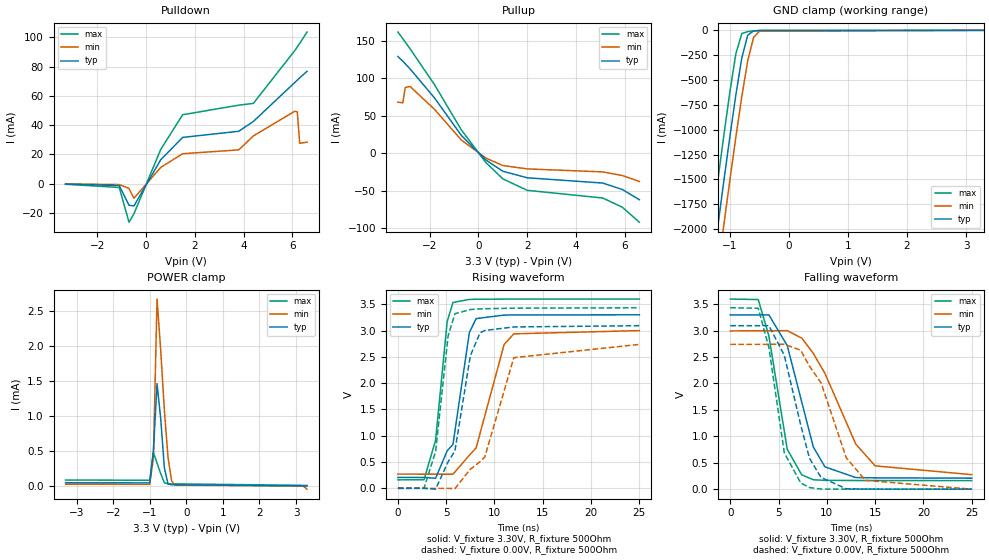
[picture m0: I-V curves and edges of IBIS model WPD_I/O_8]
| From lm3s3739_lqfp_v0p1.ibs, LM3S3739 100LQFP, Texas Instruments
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[Model]   WPD_I/O_8
Model_type   I/O
Vinl = 1.26
Vinh = 2.04
Vmeas = 1.65
| variable   typ   min   max
C_comp   9.739pF   9.739pF   9.803pF
[Model Spec]
Vinh+   1.91   1.78   2.04
Vinh-   1.90   1.76   2.03
Vinl+   1.40   1.27   1.54
Vinl-   1.39   1.26   1.53
| variable   typ   min   max
[Temperature Range]  25   85   -40
[Voltage Range]   3.3V   3.0V   3.6V
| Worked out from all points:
|   slope of the pulldown table from 0 to 0.495 V, typ, clamps not added: 35.8 ohm
|   slope of the pullup table from 0 to 0.495 V, typ, clamps not added: 35.8 ohm
|   GND clamp passes 1 mA (typ) near -0.48 V on its own axis
|   POWER clamp passes 1 mA (typ) near -0.71 V on its own axis
|   falling waveform, V_fixture 3.30V, R_fixture 500Ohm: 20-80 % time 2.57ns typ, 3.82ns min, 1.8ns max; typ from 3.3 V to 0.208 V
|   rising waveform, V_fixture 3.30V, R_fixture 500Ohm: 20-80 % time 1.54ns typ, 2.24ns min, 1.14ns max; typ from 0.208 V to 3.3 V
|   falling waveform, V_fixture 0.00V, R_fixture 500Ohm: 20-80 % time 2.29ns typ, 3.1ns min, 1.68ns max; typ from 3.09 V to 0 V
|   rising waveform, V_fixture 0.00V, R_fixture 500Ohm: 20-80 % time 1.64ns typ, 2.39ns min, 1.21ns max; typ from 0 V to 3.09 V
[Pulldown]
|  Voltage   I(typ)   I(min)   I(max)
-3.3V     -256.5uA   -145.6uA   -364.4uA
-1.1V     -1.273mA   -587.4uA   -2.566mA
-700mV    -14.71mA   -3.214mA   -26.32mA
-500mV    -15.25mA   -9.999mA   -20.65mA
600mV     16.35mA    11.13mA    23.4mA
1.5V      31.67mA    20.51mA    47.18mA
3.8V      35.87mA    23.14mA    53.71mA
4.4V      42.58mA    32.68mA    54.95mA
6.1V      69.24mA    49.59mA    91.09mA
6.2V      70.82mA    49.16mA    93.48mA
6.3V      72.4mA     27.65mA    95.95mA
6.6V      76.88mA    28.4mA     103.7mA
[Pullup]
|  Voltage   I(typ)   I(min)   I(max)
-3.3V     129.3mA    68.2mA     161.9mA
-3.1V     122.9mA    67.4mA     153.1mA
-3V       119.6mA    87.82mA    148.6mA
-2.8V     112.6mA    89.2mA     139.5mA
-1.8V     73.96mA    58.72mA    91.63mA
-700mV    23.81mA    17.72mA    31.26mA
300mV     -8.861mA   -6.312mA   -12.18mA
1V        -24.01mA   -16.38mA   -34.13mA
2V        -32.74mA   -20.87mA   -49.48mA
5.1V      -39.81mA   -24.88mA   -59.77mA
5.9V      -48.4mA    -29.75mA   -72.06mA
6.6V      -62.06mA   -37.61mA   -92.08mA
[GND Clamp]
|  Voltage   I(typ)   I(min)   I(max)
-3.3V     -11.73A    -12.14A    -11.32A
-1.4V     -2.85A     -3.29A     -2.391A
-1.3V     -2.393A    -2.835A    -1.933A
-1.2V     -1.942A    -2.383A    -1.481A
-1.1V     -1.496A    -1.937A    -1.038A
-1V       -1.061A    -1.498A    -612.1mA
-900mV    -646.5mA   -1.071A    -233.9mA
-800mV    -278.2mA   -665.9mA   -32.18mA
-700mV    -49.13mA   -307.7mA   -12.5mA
-600mV    -5.766mA   -70.86mA   -6.513mA
-500mV    -1.212mA   -8.171mA   -2.264mA
3.3V      16.11uA    11.95uA    29.77uA
[POWER Clamp]
|  Voltage   I(typ)   I(min)   I(max)
-3.3V     45.95uA    24.7uA     84.99uA
-1V       43.79uA    23.54uA    81.02uA
-900mV    497uA      400.5uA    481.3uA
-800mV    1.464mA    2.675mA    328uA
-700mV    965.7uA    1.944mA    175.8uA
-600mV    259.3uA    1.087mA    45.21uA
-500mV    29.01uA    407.8uA    31.06uA
-400mV    16.44uA    70.61uA    29.85uA
-300mV    16.12uA    11.95uA    29.79uA
3.1V      2.407uA    -925.9nA   9.193uA
3.2V      1.227uA    -4.064uA   7.471uA
3.3V      -117.9pA   -46.06uA   5.69uA
[Ramp]
| variable   typ   min   max
dV/dt_f   1.85/2.57n   1.63/3.82n   2.06/1.80n
dV/dt_r   1.86/1.64n   1.63/2.39n   2.06/1.21n
R_load = 500Ohm
[Falling Waveform]
V_fixture = 3.30V
V_fixture_min = 3.00V
V_fixture_max = 3.60V
R_fixture = 500Ohm
|   Time   V(typ)   V(min)   V(max)
0s        3.298V     2.994V     3.597V
2.9ns     3.298V     2.998V     3.588V
4ns       3.298V     2.998V     2.898V
5.9ns     2.717V     2.999V     754.8mV
7.4ns     1.65V      2.859V     271.3mV
8.6ns     799.3mV    2.568V     178.4mV
9.8ns     422.5mV    2.192V     166.9mV
13ns      219mV      852mV      163.9mV
15ns      214mV      441.3mV    163.3mV
25ns      208.2mV    274.5mV    162.3mV
[Rising Waveform]
V_fixture = 3.30V
V_fixture_min = 3.00V
V_fixture_max = 3.60V
R_fixture = 500Ohm
|   Time   V(typ)   V(min)   V(max)
0s        207.6mV    271.4mV    162.2mV
2.7ns     207.4mV    270.4mV    165.3mV
3.9ns     191.8mV    270.1mV    914mV
5.1ns     714.8mV    269.9mV    3.171V
5.7ns     836.9mV    269.3mV    3.533V
7.4ns     2.965V     630.1mV    3.591V
8.1ns     3.227V     771.5mV    3.594V
11ns      3.294V     2.736V     3.597V
12ns      3.296V     2.937V     3.597V
25ns      3.299V     2.999V     3.598V
[Falling Waveform]
V_fixture = 0.00V
V_fixture_min = 0.00V
V_fixture_max = 0.00V
R_fixture = 500Ohm
|   Time   V(typ)   V(min)   V(max)
0s        3.093V     2.739V     3.433V
2.9ns     3.093V     2.74V      3.423V
4ns       3.094V     2.741V     2.68V
5.6ns     2.532V     2.741V     685.6mV
7.3ns     1.21V      2.629V     116.7mV
8.2ns     586.3mV    2.327V     30.35mV
9.4ns     222.8mV    2.013V     1.741mV
12ns      7.855mV    597.6mV    107.7uV
14ns      1.389mV    166.7mV    70.3uV
25ns      37.48uV    42.83uV    16.46uV
[Rising Waveform]
V_fixture = 0.00V
V_fixture_min = 0.00V
V_fixture_max = 0.00V
R_fixture = 500Ohm
|   Time   V(typ)   V(min)   V(max)
0s        364.4uV    12.24mV    108.2uV
2.7ns     122.3uV    1.727mV    4.268mV
3.9ns     -14.91mV   677.3uV    699.6mV
5.2ns     506.2mV    277.7uV    2.901V
5.9ns     711.2mV    -6.26mV    3.319V
7.5ns     2.521V     363.7mV    3.399V
8.5ns     2.956V     507.8mV    3.411V
9ns       3.001V     598.7mV    3.414V
12ns      3.068V     2.484V     3.425V
25ns      3.092V     2.736V     3.432V
